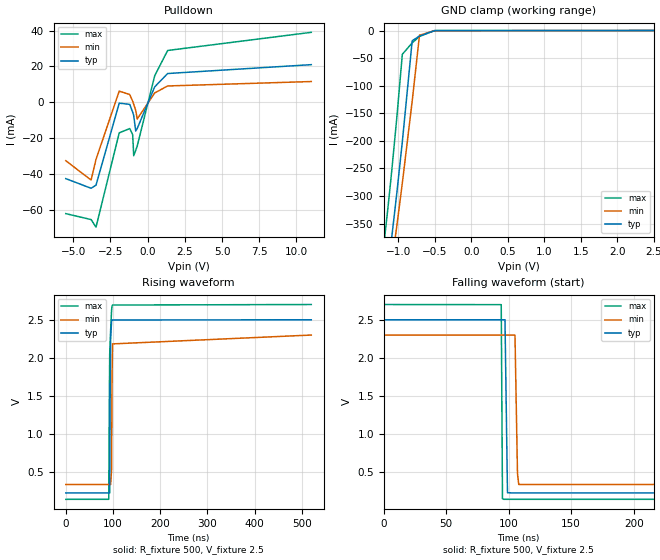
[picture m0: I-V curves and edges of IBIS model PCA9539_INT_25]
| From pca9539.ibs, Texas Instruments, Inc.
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[Model]   PCA9539_INT_25
Model_type  Open_drain
Enable   Active-Low
Vref =   2.5V
Rref =   1k
Cref =   50p
Vmeas =   1.25
| variable   typ   min   max
C_comp   1.63pF   1.31pF   2.82pF
| C_pulldown   2.02pF   1.59pF   3.19pF
| C_tri-state   1.63pF   1.31pF   2.82pF
[Temperature Range]   40   100   -40
| Ambient temperature   25   85   -40
[Voltage range]   2.5   2.3   2.7
[Pullup Reference]   2.5   2.5   2.5
[POWER Clamp Reference]   2.5   2.5   2.5
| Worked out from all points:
|   slope of the pulldown table from 0 to 0.375 V, typ, clamps not added: 53.7 ohm
|   GND clamp passes 1 mA (typ) near -0.54 V on its own axis
|   rising waveform, R_fixture 500, V_fixture 2.5: 20-80 % time 1.35ns typ, 1.16ns min, 2.43ns max; typ from 0.232 V to 2.5 V
|   falling waveform, R_fixture 500, V_fixture 2.5: 20-80 % time 1.2ns typ, 768ps min, 602ps max; typ from 2.5 V to 0.232 V
[GND Clamp]
| PCA9539_INT_25
|   Voltage   I(typ)   I(min)   I(max)
-5.5V     -2.311A    -2.336A    -2.193A
-1.25V    -543.5mA   -570.3mA   -448.7mA
-1.215V   -508.3mA   -539mA     -408.9mA
-1.14V    -429.8mA   -470.1mA   -318.6mA
-1.105V   -391.5mA   -436.9mA   -273.9mA
-1.085V   -369.2mA   -417.7mA   -247.5mA
-1.02V    -294.1mA   -353.7mA   -157.3mA
-945mV    -201.8mA   -276.7mA   -43.17mA
-810mV    -18.59mA   -128.2mA   -22.39mA
-710mV    -10.03mA   -8.507mA   -10.85mA
-505mV    -303uA     -441.4uA   -42.12uA
2.5V      81.17pA    241pA      55.18pA
[Pulldown]
| PCA9539_INT_25
|   Voltage   I(typ)   I(min)   I(max)
-5.5V     -42.74mA   -32.74mA   -62.3mA
-3.8V     -48.13mA   -43.54mA   -65.6mA
-3.47V    -46.4mA    -31.98mA   -69.85mA
-1.91V    -577uA     6.142mA    -17.17mA
-1.205V   -1.26mA    4.254mA    -14.77mA
-1.005V   -5.6mA     469uA      -18.19mA
-935mV    -7.529mA   -1.17mA    -29.92mA
-800mV    -16.18mA   -4.649mA   -26.95mA
-700mV    -14.75mA   -9.44mA    -24.52mA
475mV     8.521mA    5.134mA    14.72mA
1.345V    15.98mA    9.024mA    28.85mA
11V       20.93mA    11.5mA     38.99mA
[Ramp]
| PCA9539_INT_25
| variable   typ   min   max
dV/dt_r   1.36/1.00E-09   1.18/1.07E-09   1.53/2.12E-09
dV/dt_f   1.37/3.27E-10   1.18/6.69E-10   1.54/1.64E-10
R_load = 500
[Rising Waveform]
| PCA9539_INT_25
R_fixture =   500
C_fixture =   0
L_fixture =   0
V_fixture =   2.5
V_fixture_min = 2.3
V_fixture_max = 2.7
|   Time   V(typ)   V(min)   V(max)
0s        231.7mV    342.8mV    148.5mV
91ns      231.7mV    342.8mV    148.5mV
92ns      231.7mV    342.8mV    1.3V
93ns      233.1mV    342.8mV    2.049V
94ns      1.577V     342.8mV    2.21V
95ns      2.263V     342.8mV    2.367V
97ns      2.488V     536.4mV    2.627V
98ns      2.498V     1.778V     2.678V
99ns      2.497V     2.184V     2.693V
520ns     2.5V       2.3V       2.7V
[Falling Waveform]
| PCA9539_INT_25
R_fixture =   500
C_fixture =   0
L_fixture =   0
V_fixture =   2.5
V_fixture_min = 2.3
V_fixture_max = 2.7
|   Time   V(typ)   V(min)   V(max)
0s        2.5V       2.3V       2.7V
94ns      2.5V       2.3V       2.698V
95ns      2.5V       2.3V       156.3mV
96ns      2.5V       2.3V       148.4mV
97ns      2.5V       2.3V       148.9mV
99ns      234.5mV    2.3V       148.8mV
105ns     232.1mV    2.299V     148.7mV
107ns     232.1mV    485.9mV    148.7mV
108ns     232.1mV    343.4mV    148.7mV
520ns     231.7mV    342.8mV    148.5mV
